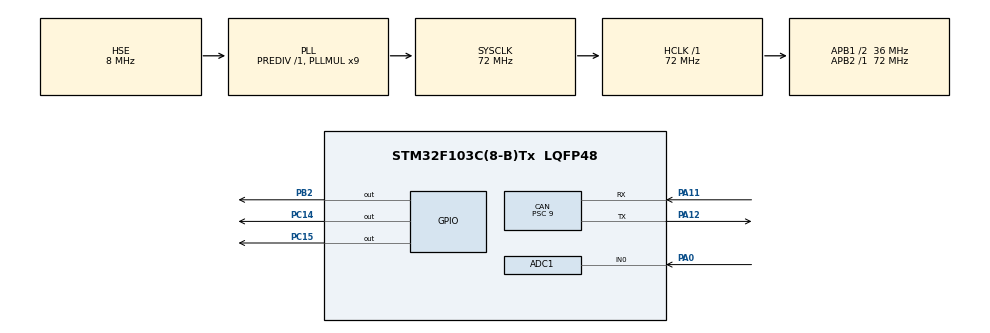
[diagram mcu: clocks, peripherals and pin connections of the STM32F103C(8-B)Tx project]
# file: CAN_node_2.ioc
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ADC1.Channel-0\#ChannelRegularConversion=ADC_CHANNEL_0
ADC1.NbrOfConversionFlag=1
ADC1.Rank-0\#ChannelRegularConversion=1
ADC1.SamplingTime-0\#ChannelRegularConversion=ADC_SAMPLETIME_239CYCLES_5
ADC1.master=1
CAN.BS1=CAN_BS1_3TQ
CAN.BS2=CAN_BS2_4TQ
CAN.CalculateBaudRate=500000
CAN.CalculateTimeBit=2000.00
CAN.CalculateTimeQuantum=250.0
CAN.Prescaler=9
FREERTOS.Queues01=q_light_msg,32,uint16_t,0,Dynamic,NULL,NULL
FREERTOS.Tasks01=recieve_msg,0,128,StartDefaultTask,Default,NULL,Dynamic,NULL,NULL;control_light,0,128,StartTask02,Default,NULL,Dynamic,NULL,NULL
Mcu.Family=STM32F1
Mcu.Name=STM32F103C(8-B)Tx
Mcu.Package=LQFP48
NVIC.PriorityGroup=NVIC_PRIORITYGROUP_4
NVIC.TIM2_IRQn=true\:5\:0\:false\:false\:true\:true\:true\:true
NVIC.USB_LP_CAN1_RX0_IRQn=true\:5\:0\:false\:false\:true\:true\:true\:true
PA0-WKUP.Signal=ADCx_IN0
PA11.Mode=CAN_Activate
PA11.Signal=CAN_RX
PA12.Mode=CAN_Activate
PA12.Signal=CAN_TX
PA13.Mode=Serial_Wire
PA13.Signal=SYS_JTMS-SWDIO
PA14.Mode=Serial_Wire
PA14.Signal=SYS_JTCK-SWCLK
PB2.Signal=GPIO_Output
PC14-OSC32_IN.Signal=GPIO_Output
PC15-OSC32_OUT.Signal=GPIO_Output
PD0-OSC_IN.Mode=HSE-External-Oscillator
PD0-OSC_IN.Signal=RCC_OSC_IN
PD1-OSC_OUT.Mode=HSE-External-Oscillator
PD1-OSC_OUT.Signal=RCC_OSC_OUT
ProjectManager.HeapSize=0x200
ProjectManager.StackSize=0x400
ProjectManager.TargetToolchain=STM32CubeIDE
RCC.ADCPresc=RCC_ADCPCLK2_DIV6
RCC.AHBFreq_Value=72000000
RCC.APB1CLKDivider=RCC_HCLK_DIV2
RCC.APB1Freq_Value=36000000
RCC.APB1TimFreq_Value=72000000
RCC.APB2Freq_Value=72000000
RCC.APB2TimFreq_Value=72000000
RCC.HCLKFreq_Value=72000000
RCC.PLLMUL=RCC_PLL_MUL9
RCC.PLLSourceVirtual=RCC_PLLSOURCE_HSE
RCC.SYSCLKFreq_VALUE=72000000
RCC.SYSCLKSource=RCC_SYSCLKSOURCE_PLLCLK
RCC.USBFreq_Value=72000000
SH.ADCx_IN0.0=ADC1_IN0,IN0
TIM2.Period=10000-1
TIM2.Prescaler=72-1
VP_FREERTOS_VS_CMSIS_V1.Mode=CMSIS_V1
VP_TIM2_VS_ClockSourceINT.Mode=Internal
board=custom

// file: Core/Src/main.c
/* USER CODE BEGIN Header */
/**
  ******************************************************************************
  * @file           : main.c
  * @brief          : Main program body
  ******************************************************************************
  * @attention
  *
  * <h2><center>&copy; Copyright (c) 2025 STMicroelectronics.
  * All rights reserved.</center></h2>
  *
  * This software component is licensed by ST under BSD 3-Clause license,
  * the "License"; You may not use this file except in compliance with the
  * License. You may obtain a copy of the License at:
  *                        opensource.org/licenses/BSD-3-Clause
  *
  ******************************************************************************
  */
/* USER CODE END Header */
#include "main.h"
#include "cmsis_os.h"

/* USER CODE BEGIN Includes */
#include "can_handler.h"
/* USER CODE END Includes */

ADC_HandleTypeDef hadc1;

CAN_HandleTypeDef hcan;

TIM_HandleTypeDef htim2;

osThreadId recieve_msgHandle;
osThreadId control_lightHandle;
osMessageQId q_light_msgHandle;
/* USER CODE BEGIN PV */

uint8_t light_msg = 0;
enum light_mode_t light_mode;

CAN_TxHeaderTypeDef   tx_header;
uint8_t               tx_data[8];
uint32_t              tx_mailbox;

CAN_RxHeaderTypeDef   rx_header;
uint8_t               rx_data[8];
/* USER CODE END PV */

void SystemClock_Config(void);
static void MX_GPIO_Init(void);
static void MX_CAN_Init(void);
static void MX_TIM2_Init(void);
static void MX_ADC1_Init(void);
void StartDefaultTask(void const * argument);
void StartTask02(void const * argument);

/* USER CODE BEGIN PFP */

/* Helper function to send CAN message with retry */
HAL_StatusTypeDef can_send_message(uint32_t std_id, uint8_t* data, uint8_t dlc)
{
    tx_header.StdId = std_id;
    tx_header.RTR = CAN_RTR_DATA;
    tx_header.DLC = dlc;

    /* Use retry mechanism for reliable transmission */
    return CAN_Send_WithRetry(&hcan, &tx_header, data, &tx_mailbox, CAN_RETRY_MAX);
}

void HAL_TIM_PeriodElapsedCallback(TIM_HandleTypeDef *htim)
{
	static uint8_t period_signal_cnt = 0;

	if (htim->Instance == htim2.Instance)
	{
		if (period_signal_cnt > 49)
		{
			period_signal_cnt = 0;
			control_light_IT();

			/* Send with retry mechanism */
			if (can_send_message(0x211, &light_msg, 1) != HAL_OK)
			{
			    /* Handle transmission error */
			}
		}
		period_signal_cnt++;
	}
}

void control_light_IT ()
{
	switch (light_mode)
	{
	case stop_light:
		HAL_GPIO_WritePin(GPIOB, GPIO_PIN_12, GPIO_PIN_RESET);
		HAL_GPIO_WritePin(GPIOB, GPIO_PIN_13, GPIO_PIN_RESET);
		break;

	case light_hazard:
		HAL_GPIO_TogglePin(GPIOB, GPIO_PIN_12);
		HAL_GPIO_TogglePin(GPIOB, GPIO_PIN_13);
		break;

	case light_left:
		HAL_GPIO_TogglePin(GPIOB, GPIO_PIN_12);
		HAL_GPIO_WritePin(GPIOB, GPIO_PIN_13, GPIO_PIN_RESET);
		break;

	case light_right:
		HAL_GPIO_WritePin(GPIOB, GPIO_PIN_12, GPIO_PIN_RESET);
		HAL_GPIO_TogglePin(GPIOB, GPIO_PIN_13);
		break;

	default:
		HAL_GPIO_WritePin(GPIOB, GPIO_PIN_12, GPIO_PIN_RESET);
		HAL_GPIO_WritePin(GPIOB, GPIO_PIN_13, GPIO_PIN_RESET);
		light_mode = stop_light;
		break;
	}

}

void light_mgs_parse (uint8_t light_mode_msg)
{
	HAL_GPIO_WritePin(GPIOB, GPIO_PIN_12, GPIO_PIN_RESET);
	HAL_GPIO_WritePin(GPIOB, GPIO_PIN_13, GPIO_PIN_RESET);
	if ((light_mode_msg >> 0) & 0x01)
	{
		light_mode = stop_light;
		HAL_TIM_Base_Stop_IT(&htim2);
	}

	if ((light_mode_msg >> 1) & 0x01)
	{
		light_mode = light_hazard;
		HAL_TIM_Base_Start_IT(&htim2);
	}
	else if ((light_mode_msg >> 2) & 0x01)
	{
		light_mode = light_left;
		HAL_TIM_Base_Start_IT(&htim2);
	}
	else if ((light_mode_msg >> 3) & 0x01)
	{
		light_mode = light_right;
		HAL_TIM_Base_Start_IT(&htim2);
	}
	else
	{
		light_mode = stop_light;
		HAL_TIM_Base_Stop_IT(&htim2);

		tx_header.StdId = 0x211;
		tx_header.RTR = CAN_RTR_DATA;
		tx_header.DLC = 1;
		if (HAL_CAN_AddTxMessage(&hcan, &tx_header, &light_mode_msg, &tx_mailbox) != HAL_OK)
		{
		   Error_Handler ();
		}
	}

	if ((light_mode_msg >> 4) & 0x01)
	{
		/* T.B.D */
	}

	if ((light_mode_msg >> 5) & 0x01)
	{
		/* T.B.D */
	}

	if ((light_mode_msg >> 6) & 0x01)
	{
		/* T.B.D */
	}

	if ((light_mode_msg >> 7) & 0x01)
	{
		/* T.B.D */
	}
}

void clear_buff (uint8_t * buff_clear, size_t num)
{
	if (buff_clear == NULL) return;

	memset(buff_clear, 0, num);
}

void HAL_CAN_RxFifo0MsgPendingCallback(CAN_HandleTypeDef *hcan)
{
	  if (HAL_CAN_GetRxMessage(hcan, CAN_RX_FIFO0, &rx_header, rx_data) != HAL_OK)
	  {
	    Error_Handler();
	  }
	  if (rx_header.StdId == 0x210)
	  {
		  osMessagePut(q_light_msgHandle, rx_data[0], 0);
	  }
	  clear_buff(&rx_data, sizeof(uint8_t)*8);
}

/* USER CODE END PFP */

int main(void)
{

  /* MCU Configuration--------------------------------------------------------*/

  /* Reset of all peripherals, Initializes the Flash interface and the Systick. */
  HAL_Init();

  /* Configure the system clock */
  SystemClock_Config();

  /* Initialize all configured peripherals */
  MX_GPIO_Init();
  MX_CAN_Init();
  MX_TIM2_Init();
  MX_ADC1_Init();
  /* USER CODE BEGIN 2 */
  /* Initialize CAN error handler */
  CAN_ErrorHandler_Init(&hcan);

  HAL_CAN_Start(&hcan);

  /* Activate CAN notifications with error handling */
  HAL_CAN_ActivateNotification(&hcan,
      CAN_IT_RX_FIFO0_MSG_PENDING |
      CAN_IT_ERROR_WARNING |
      CAN_IT_ERROR_PASSIVE |
      CAN_IT_BUSOFF |
      CAN_IT_LAST_ERROR_CODE);

  /* USER CODE END 2 */

  /* Create the queue(s) */
  /* definition and creation of q_light_msg */
  osMessageQDef(q_light_msg, 32, uint16_t);
  q_light_msgHandle = osMessageCreate(osMessageQ(q_light_msg), NULL);

  /* Create the thread(s) */
  /* definition and creation of recieve_msg */
  osThreadDef(recieve_msg, StartDefaultTask, osPriorityNormal, 0, 128);
  recieve_msgHandle = osThreadCreate(osThread(recieve_msg), NULL);

  /* definition and creation of control_light */
  osThreadDef(control_light, StartTask02, osPriorityNormal, 0, 128);
  control_lightHandle = osThreadCreate(osThread(control_light), NULL);

  /* Start scheduler */
  osKernelStart();

  /* We should never get here as control is now taken by the scheduler */
  /* Infinite loop */
  while (1)
  {

  }
}

void SystemClock_Config(void)
{
  RCC_OscInitTypeDef RCC_OscInitStruct = {0};
  RCC_ClkInitTypeDef RCC_ClkInitStruct = {0};
  RCC_PeriphCLKInitTypeDef PeriphClkInit = {0};

  /** Initializes the RCC Oscillators according to the specified parameters
  * in the RCC_OscInitTypeDef structure.
  */
  RCC_OscInitStruct.OscillatorType = RCC_OSCILLATORTYPE_HSE;
  RCC_OscInitStruct.HSEState = RCC_HSE_ON;
  RCC_OscInitStruct.HSEPredivValue = RCC_HSE_PREDIV_DIV1;
  RCC_OscInitStruct.HSIState = RCC_HSI_ON;
  RCC_OscInitStruct.PLL.PLLState = RCC_PLL_ON;
  RCC_OscInitStruct.PLL.PLLSource = RCC_PLLSOURCE_HSE;
  RCC_OscInitStruct.PLL.PLLMUL = RCC_PLL_MUL9;
  if (HAL_RCC_OscConfig(&RCC_OscInitStruct) != HAL_OK)
  {
    Error_Handler();
  }
  /** Initializes the CPU, AHB and APB buses clocks
  */
  RCC_ClkInitStruct.ClockType = RCC_CLOCKTYPE_HCLK|RCC_CLOCKTYPE_SYSCLK
                              |RCC_CLOCKTYPE_PCLK1|RCC_CLOCKTYPE_PCLK2;
  RCC_ClkInitStruct.SYSCLKSource = RCC_SYSCLKSOURCE_PLLCLK;
  RCC_ClkInitStruct.AHBCLKDivider = RCC_SYSCLK_DIV1;
  RCC_ClkInitStruct.APB1CLKDivider = RCC_HCLK_DIV2;
  RCC_ClkInitStruct.APB2CLKDivider = RCC_HCLK_DIV1;

  if (HAL_RCC_ClockConfig(&RCC_ClkInitStruct, FLASH_LATENCY_2) != HAL_OK)
  {
    Error_Handler();
  }
  PeriphClkInit.PeriphClockSelection = RCC_PERIPHCLK_ADC;
  PeriphClkInit.AdcClockSelection = RCC_ADCPCLK2_DIV6;
  if (HAL_RCCEx_PeriphCLKConfig(&PeriphClkInit) != HAL_OK)
  {
    Error_Handler();
  }
}

static void MX_ADC1_Init(void)
{

  ADC_ChannelConfTypeDef sConfig = {0};

  /** Common config
  */
  hadc1.Instance = ADC1;
  hadc1.Init.ScanConvMode = ADC_SCAN_DISABLE;
  hadc1.Init.ContinuousConvMode = DISABLE;
  hadc1.Init.DiscontinuousConvMode = DISABLE;
  hadc1.Init.ExternalTrigConv = ADC_SOFTWARE_START;
  hadc1.Init.DataAlign = ADC_DATAALIGN_RIGHT;
  hadc1.Init.NbrOfConversion = 1;
  if (HAL_ADC_Init(&hadc1) != HAL_OK)
  {
    Error_Handler();
  }
  /** Configure Regular Channel
  */
  sConfig.Channel = ADC_CHANNEL_0;
  sConfig.Rank = ADC_REGULAR_RANK_1;
  sConfig.SamplingTime = ADC_SAMPLETIME_239CYCLES_5;
  if (HAL_ADC_ConfigChannel(&hadc1, &sConfig) != HAL_OK)
  {
    Error_Handler();
  }

}

static void MX_CAN_Init(void)
{

  hcan.Instance = CAN1;
  hcan.Init.Prescaler = 9;
  hcan.Init.Mode = CAN_MODE_NORMAL;
  hcan.Init.SyncJumpWidth = CAN_SJW_1TQ;
  hcan.Init.TimeSeg1 = CAN_BS1_3TQ;
  hcan.Init.TimeSeg2 = CAN_BS2_4TQ;
  hcan.Init.TimeTriggeredMode = DISABLE;
  hcan.Init.AutoBusOff = DISABLE;
  hcan.Init.AutoWakeUp = DISABLE;
  hcan.Init.AutoRetransmission = DISABLE;
  hcan.Init.ReceiveFifoLocked = DISABLE;
  hcan.Init.TransmitFifoPriority = DISABLE;
  if (HAL_CAN_Init(&hcan) != HAL_OK)
  {
    Error_Handler();
  }
  /* USER CODE BEGIN CAN_Init 2 */
  CAN_FilterTypeDef canfilterconfig;

  canfilterconfig.FilterActivation = ENABLE;
  canfilterconfig.FilterBank = 0;
  canfilterconfig.FilterFIFOAssignment = CAN_RX_FIFO0;
  canfilterconfig.FilterMode = CAN_FILTERMODE_IDMASK;
  canfilterconfig.FilterIdHigh = 0x200 << 5;
  canfilterconfig.FilterIdLow = 0;
  canfilterconfig.FilterMaskIdHigh = 0;
  canfilterconfig.FilterMaskIdLow = 0;
  canfilterconfig.FilterScale = CAN_FILTERSCALE_32BIT;
  canfilterconfig.SlaveStartFilterBank = 10;

  HAL_CAN_ConfigFilter(&hcan, &canfilterconfig);

  /* USER CODE END CAN_Init 2 */

}

static void MX_TIM2_Init(void)
{

  TIM_ClockConfigTypeDef sClockSourceConfig = {0};
  TIM_MasterConfigTypeDef sMasterConfig = {0};

  htim2.Instance = TIM2;
  htim2.Init.Prescaler = 72-1;
  htim2.Init.CounterMode = TIM_COUNTERMODE_UP;
  htim2.Init.Period = 10000-1;
  htim2.Init.ClockDivision = TIM_CLOCKDIVISION_DIV1;
  htim2.Init.AutoReloadPreload = TIM_AUTORELOAD_PRELOAD_DISABLE;
  if (HAL_TIM_Base_Init(&htim2) != HAL_OK)
  {
    Error_Handler();
  }
  sClockSourceConfig.ClockSource = TIM_CLOCKSOURCE_INTERNAL;
  if (HAL_TIM_ConfigClockSource(&htim2, &sClockSourceConfig) != HAL_OK)
  {
    Error_Handler();
  }
  sMasterConfig.MasterOutputTrigger = TIM_TRGO_RESET;
  sMasterConfig.MasterSlaveMode = TIM_MASTERSLAVEMODE_DISABLE;
  if (HAL_TIMEx_MasterConfigSynchronization(&htim2, &sMasterConfig) != HAL_OK)
  {
    Error_Handler();
  }

}

static void MX_GPIO_Init(void)
{
  GPIO_InitTypeDef GPIO_InitStruct = {0};

  /* GPIO Ports Clock Enable */
  __HAL_RCC_GPIOC_CLK_ENABLE();
  __HAL_RCC_GPIOD_CLK_ENABLE();
  __HAL_RCC_GPIOA_CLK_ENABLE();
  __HAL_RCC_GPIOB_CLK_ENABLE();

  /*Configure GPIO pin Output Level */
  HAL_GPIO_WritePin(GPIOC, GPIO_PIN_14|GPIO_PIN_15, GPIO_PIN_RESET);

  /*Configure GPIO pin Output Level */
  HAL_GPIO_WritePin(GPIOB, GPIO_PIN_2|GPIO_PIN_12|GPIO_PIN_13, GPIO_PIN_RESET);

  /*Configure GPIO pins : PC14 PC15 */
  GPIO_InitStruct.Pin = GPIO_PIN_14|GPIO_PIN_15;
  GPIO_InitStruct.Mode = GPIO_MODE_OUTPUT_PP;
  GPIO_InitStruct.Pull = GPIO_NOPULL;
  GPIO_InitStruct.Speed = GPIO_SPEED_FREQ_LOW;
  HAL_GPIO_Init(GPIOC, &GPIO_InitStruct);

  /*Configure GPIO pins : PB2 PB12 PB13 */
  GPIO_InitStruct.Pin = GPIO_PIN_2|GPIO_PIN_12|GPIO_PIN_13;
  GPIO_InitStruct.Mode = GPIO_MODE_OUTPUT_PP;
  GPIO_InitStruct.Pull = GPIO_NOPULL;
  GPIO_InitStruct.Speed = GPIO_SPEED_FREQ_LOW;
  HAL_GPIO_Init(GPIOB, &GPIO_InitStruct);

}

void StartDefaultTask(void const * argument)
{
  /* USER CODE BEGIN 5 */
  /* Infinite loop */
  for(;;)
  {
	HAL_GPIO_TogglePin(GPIOC, GPIO_PIN_13);
	osDelay(1000);
  }
  /* USER CODE END 5 */
}

uint32_t can_esr;
uint8_t tec;
uint8_t rec ;
uint8_t last_error;

void StartTask02(void const * argument)
{
  /* USER CODE BEGIN StartTask02 */
  /* Infinite loop */
	osEvent q_message;
  for(;;)
  {
	  can_esr = hcan.Instance->ESR;
	  tec = (uint8_t)((can_esr & CAN_ESR_TEC_Msk) >> CAN_ESR_TEC_Pos);
	   rec = (uint8_t)((can_esr & CAN_ESR_REC_Msk) >> CAN_ESR_REC_Pos);
	   last_error = (uint8_t)((can_esr & CAN_ESR_LEC_Msk) >> CAN_ESR_LEC_Pos);

	  /* get element from light queue to send light node control light */
	q_message = osMessageGet(q_light_msgHandle, 0);

	/* get a message in q_light_control if it is not empty */
	if (q_message.status == osEventMessage)
	{
		light_msg = q_message.value.v;
		light_mgs_parse(light_msg);
	}
	osDelay(10);
  }
  /* USER CODE END StartTask02 */
}

void Error_Handler(void)
{
  __disable_irq();
  while (1)
  {
  }
}

/************************ (C) COPYRIGHT STMicroelectronics *****END OF FILE****/
